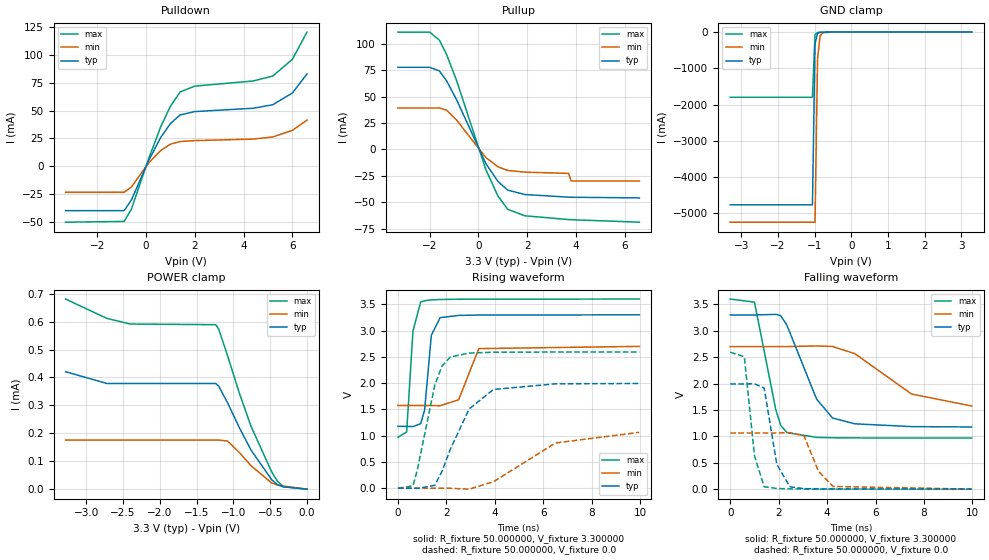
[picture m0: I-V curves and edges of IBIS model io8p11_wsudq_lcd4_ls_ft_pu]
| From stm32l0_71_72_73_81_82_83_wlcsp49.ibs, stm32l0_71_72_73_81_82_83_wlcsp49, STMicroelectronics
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|   Model io8p11_wsudq_lcd4_ls_ft_pu
[Model]  io8p11_wsudq_lcd4_ls_ft_pu
Model_type I/O
Polarity   Non-Inverting
Enable   Active-Low
Vinl =   0.990000V
Vinh =   2.310000V
Vmeas =  1.650000V
Cref =   50.000000pF
Rref =   100.000000M
Vref =   0.0V
C_comp   3.263700pF   3.224800pF   3.309000pF
[Temperature Range]   25.000000   0.125000k   -40.000000
[Pullup Reference]   3.300000V   2.700000V   3.600000V
[Pulldown Reference]   0.0V   0.0V   0.0V
[POWER Clamp Reference]   3.300000V   2.700000V   3.600000V
[GND Clamp Reference]   0.0V   0.0V   0.0V
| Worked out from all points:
|   slope of the pulldown table from 0 to 0.495 V, typ, clamps not added: 22.6 ohm
|   slope of the pullup table from 0 to 0.495 V, typ, clamps not added: 23.9 ohm
|   GND clamp passes 1 mA (typ) near -0.64 V on its own axis
|   rising waveform, R_fixture 50.000000, V_fixture 3.300000: 20-80 % time 239ps typ, 377ps min, 201ps max; typ from 1.18 V to 3.3 V
|   rising waveform, R_fixture 50.000000, V_fixture 0.0: 20-80 % time 1.2ns typ, 2.21ns min, 720ps max; typ from 0.001 V to 1.99 V
|   falling waveform, R_fixture 50.000000, V_fixture 3.300000: 20-80 % time 1.13ns typ, 2.03ns min, 654ps max; typ from 3.3 V to 1.18 V
|   falling waveform, R_fixture 50.000000, V_fixture 0.0: 20-80 % time 424ps typ, 589ps min, 345ps max; typ from 1.99 V to 0.001 V
[Pulldown]
|Voltage   I(typ)   I(min)   I(max)
-3.3V     -39.83mA   -23.37mA   -50.2mA
-900mV    -39.83mA   -23.37mA   -49.52mA
-600mV    -30.28mA   -18.59mA   -38.45mA
100mV     4.867mA    2.821mA    6.48mA
600mV     25.85mA    14.17mA    35.39mA
1V        38.33mA    19.81mA    53.88mA
1.4V      46.1mA     22.18mA    66.72mA
2V        49.07mA    23.02mA    71.93mA
4.4V      52.05mA    24.38mA    76.53mA
5.2V      55.25mA    26.31mA    81.02mA
6V        65.78mA    32.24mA    95.96mA
6.6V      82.83mA    41.41mA    120.4mA
[Pullup]
|Voltage   I(typ)   I(min)   I(max)
-3.3V     77.64mA    39.15mA    111mA
-2V       77.64mA    39.15mA    111mA
-1.6V     74.25mA    39.15mA    103.3mA
-1.3V     64.67mA    37mA       89.48mA
-900mV    47.24mA    27.86mA    65.53mA
300mV     -13.29mA   -7.65mA    -18.99mA
800mV     -30.32mA   -16.54mA   -44.19mA
1.2V      -38.62mA   -20mA      -56.79mA
1.9V      -42.8mA    -21.61mA   -62.92mA
3.7V      -45.29mA   -22.8mA    -66.51mA
3.8V      -45.39mA   -30mA      -66.64mA
6.6V      -46.01mA   -30mA      -69mA
[GND_clamp]
|Voltage   I(typ)   I(min)   I(max)
-3.3V     -4.767A    -5.245A    -1.798A
-1.06V    -4.767A    -5.245A    -1.798A
-990mV    -327.3mA   -5.245A    -68.38mA
-920mV    -29.22mA   -722.7mA   -11.24mA
-850mV    -6.771mA   -104.4mA   -6.721mA
-780mV    -3.56mA    -17.38mA   -4.326mA
-500mV    -59.41uA   -172uA     -34.91uA
3.28V     0A         0A         0A
[POWER_clamp]
|Voltage   I(typ)   I(min)   I(max)
-3.28V    420.5uA    175.8uA    680.7uA
-2.72V    378.4uA    175.8uA    611.5uA
-2.4V     378.3uA    175.8uA    591.3uA
-1.24V    378.3uA    175.8uA    588.9uA
-1.2V     368.9uA    175.8uA    573.6uA
-1.08V    309.6uA    172.2uA    478.3uA
-920mV    220.5uA    131.5uA    344.5uA
-760mV    139.7uA    83.77uA    224.7uA
-480mV    33.95uA    22.2uA     61.82uA
-400mV    15.86uA    14.75uA    27.74uA
-320mV    8.148uA    10.83uA    9.341uA
0V        0A         0A         0A
[Ramp]
| variable   typ   min   max
dV/dt_r  1.19402/1.19340n   0.61049/2.09112n   1.55517/0.71953n
dV/dt_f  1.27116/1.13123n   0.59064/1.82716n   1.57796/0.65280n
R_load = 50.000000
[Rising Waveform]
R_fixture= 50.000000
V_fixture= 3.300000
V_fixture_min= 2.700000
V_fixture_max= 3.600000
|time   V(typ)   V(min)   V(max)
0s        1.178V     1.575V     968.7mV
360.4ps   1.177V     1.575V     1.072V
620.6ps   1.174V     1.575V     2.991V
940.9ps   1.229V     1.575V     3.546V
1.101ns   1.486V     1.575V     3.569V
1.381ns   2.913V     1.574V     3.584V
1.742ns   3.246V     1.57V      3.592V
2.503ns   3.289V     1.683V     3.597V
3.343ns   3.296V     2.657V     3.599V
9.97ns    3.3V       2.7V       3.6V
[Rising Waveform]
R_fixture= 50.000000
V_fixture= 0.0
V_fixture_min= 0.0
V_fixture_max= 0.0
|time   V(typ)   V(min)   V(max)
0s        1.058mV    1.825mV    424.3uV
620.6ps   340.2uV    1.81mV     45.24mV
800.8ps   -3.419mV   1.818mV    348.4mV
1.522ns   55.62mV    1.991mV    1.963V
1.822ns   322.1mV    1.566mV    2.326V
2.162ns   742.3mV    -798.9uV   2.497V
2.943ns   1.508V     -17.5mV    2.573V
3.944ns   1.88V      123.5mV    2.588V
6.507ns   1.987V     861.7mV    2.592V
9.97ns    1.993V     1.064V     2.593V
[Falling Waveform]
R_fixture= 50.000000
V_fixture= 3.300000
V_fixture_min= 2.700000
V_fixture_max= 3.600000
|time   V(typ)   V(min)   V(max)
0s        3.3V       2.7V       3.6V
1.001ns   3.299V     2.7V       3.541V
1.882ns   3.31V      2.7V       1.501V
2.082ns   3.286V     2.7V       1.209V
2.342ns   3.102V     2.7V       1.071V
3.564ns   1.707V     2.712V     981.1mV
4.224ns   1.347V     2.702V     974.3mV
5.145ns   1.238V     2.566V     970.9mV
7.487ns   1.185V     1.802V     969mV
9.97ns    1.178V     1.575V     968.7mV
[Falling Waveform]
R_fixture= 50.000000
V_fixture= 0.0
V_fixture_min= 0.0
V_fixture_max= 0.0
|time   V(typ)   V(min)   V(max)
0s        1.993V     1.064V     2.593V
580.6ps   1.992V     1.064V     2.508V
1.001ns   1.996V     1.064V     629.6mV
1.401ns   1.916V     1.064V     45.96mV
1.922ns   472.6mV    1.064V     12.98mV
2.462ns   45.69mV    1.071V     5.466mV
3.043ns   10.36mV    1.012V     2.69mV
3.644ns   5.263mV    337.9mV    1.769mV
4.244ns   3.476mV    51.2mV     1.278mV
9.97ns    1.058mV    1.825mV    424.3uV
